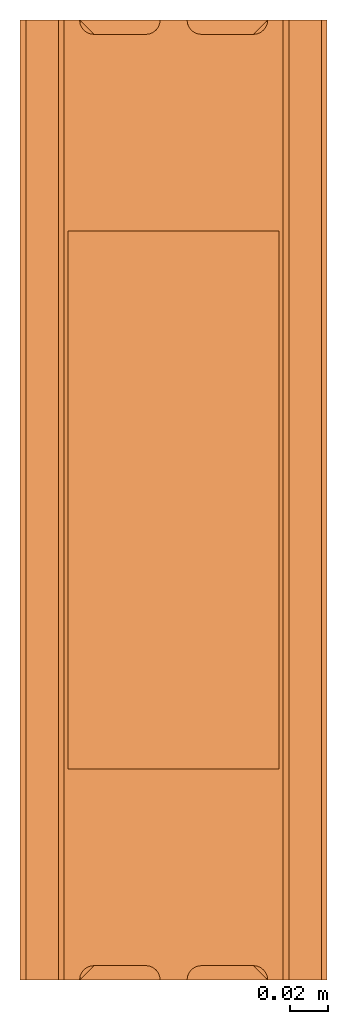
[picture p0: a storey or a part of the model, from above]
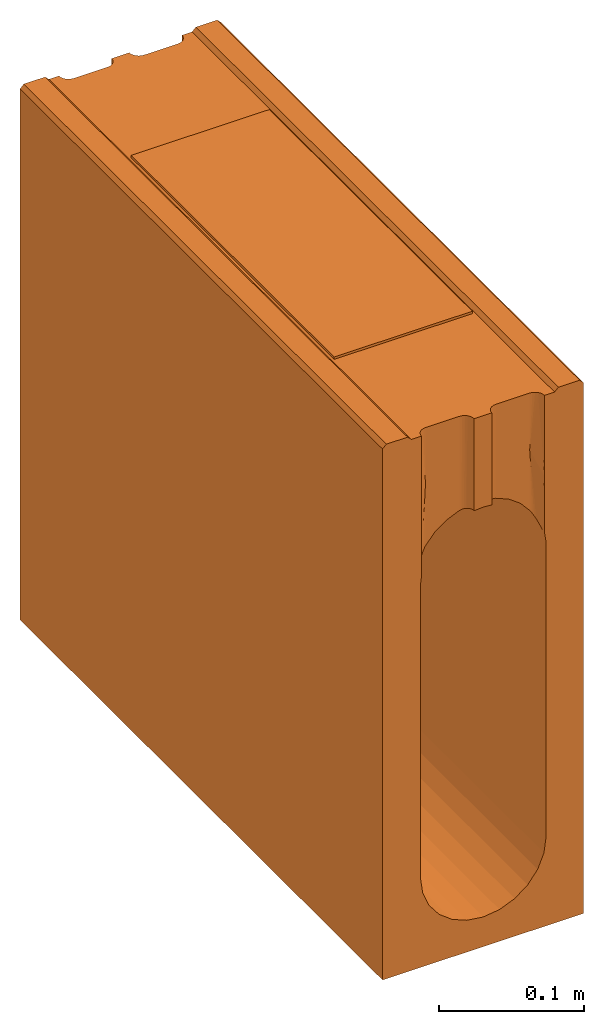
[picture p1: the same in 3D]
Properties of the parts of a building model (IFC2X3)

# File
Description: ViewDefinition [CoordinationView]
File name: 32503 - PD100 F 50.3 Rodding Access 500mm LG.ifc
Time: 2013-10-11T12:33:49
Written by: Autodesk Revit 2013
Made in: 20120221_2030(x64)

# IfcProject, Project Number
LongName: Project Name; Phase: Project Status

# IfcSite, Default
RefLatitude: 42, 21, 30, 344238; RefLongitude: -71, -3, -35, -194702; RefElevation: 0 mm

# IfcBuilding
Pset_BuildingCommon - NumberOfStoreys: 2
Other - Client Name: Owner; Project Number: Project Number; Project Issue Date: Issue Date; Project Status: Project Status; Project Address: Enter address here; Project Name: Project Name

# IfcBuildingStorey (2)
Constraints - Elevation Base: 0
Graphics - Symbol: M_Level Head - Circle: M_Level Head - Circle; Color: 0; Line Pattern: Center; Symbol at End 1 Default: no; Symbol at End 2 Default: yes; Line Weight: 1
Identity Data - Building Story: yes; Structural: no
Dimensions - Computation Height: 0 mm
Name | LongName = Name | Elevation (mm) = Constraints, Elevation (mm)
B.O. Footing | B.O. Footing | -4600
T.O. Footing | T.O. Footing | -4300

# IfcBuildingElementProxy: 32503 - PD100 F 50.3 Rodding Access 500mm LG, Civil-Drainage-Channel-ACO-RoadDrain 100:32503 - PD100 F 50.3 Rodding Access 500mm LG:32503 - PD100 F 50.3 Rodding Access 500mm LG:310733
In: B.O. Footing
Material: Acetal Resin, Black
Other - Revision: 1; CreatedBy: www.aco.co.uk
Dimensions - Invert Depth.: 375 mm; Void Depth: -450 mm; I/O End Cap Void: 3260 mm; Straight Void Start: 0 mm; Total Depth: 450 mm; Custom Void Length: 0 mm; Volume: 19568456 mm3; Straight Void Length: 500 mm; Length: 500 mm
Phasing - Phase Created: Phase 1
Constraints - Level: Level: T.O. Footing; Moves With Nearby Elements: no
Pset_BuildingElementProxyCommon - Reference: 32503 - PD100 F 50.3 Rodding Access 500mm LG
Identity Data - URL: www.aco.co.uk; Product Page URL: http://www.aco.co.uk/product_detail.php?id=21; Type Comments: ACO RoadDrain 100 PD100F 50.3 Constant Depth Access Channel 500mm Long; OmniClass Title: Rainwater Removal; Manufacturer: ACO Technologies plc - ACO Water Management Division; Cost: 0; Model: ACO RoadDrain 100 PD100F; Assembly Code: D2040; e-mail Technical: technical@aco.co.uk; OmniClass Number: 23.70.50.24; Installation guidelines: http://www.aco.co.uk/download.php?id=256; Address: ACO Business Park, Hitchin Road, Shefford, Bedfordshire, United Kingdom SG17 5TE; Product Code: 32503; e-mail Sales: customersupport@aco.co.uk; Model Description: Monolithic Channel drainage system; Price: POA - contact ACO; Maintenance guidelines: http://www.aco.co.uk/download.php?id=256; Watermarked With: BIM Manager Premium Suite; Watermark 1: This file is the property of ACO Technologies PLC; Telephone: +44 (0)1462 816666; Assembly Description: Rain Water Drainage; Watermark 2: This file is water marked and users are prohibited to reproduce, adapt, distribute this information; Fax: +44 (0)1462 815895; Product brochure: http://www.aco.co.uk/download.php?id=256; Watermarked By: www.aco.co.uk
Data - Product Dimensions: 500mm x 160mm x 450mm (LxWxH); Invert Depth: 425mm; Installation - Concrete Grade: Refer to brochure; Concrete Surround Volume - Load Class F 900 - Concrete Pavement: 0.30m³; Connection Pipe O.D: N/A; ACO Hydraulic Design Software: http://www.acodesign.co.uk; Load Class: A 15 - F 900; Channel C.S.A: 0.032m²; Hydraulic Performance: http://www.aco.co.uk/download.php?id=256; Product Weight: 34.6 Kg; Product Standard: BE EN1433:2002, CE Marked, Kitemarked
General - TagNumber: 0.000000; SerialNumber: 0.000000
Materials and Finishes - Access Cover/Frame Finish: Water Based Paint Coating; Grating Material: N/A; Access Cover/Frame Material: Ductile Iron; End Cap Material: N/A; Connection Pipe Material: N/A; Grating Colour: N/A; Grating Finish: N/A; Access Cover/Frame Colour: Black; Channel Colour: Black; End Cap Colour: N/A; Connection Pipe Colour: N/A; Channel Material: Vienite® Synthetic Resin Concrete
Green Building Properties - Channel Recyclable: Fully recyclable; Access Cover/Frame Recyclable: Fully recyclable; Access Cover/Frame Recycled Material Content: Between 40% - 90%; Grating Recycled Material Content: N/A; Channel Recycled Material Content: 20% minimum; Grating Recyclable: N/A; End Cap Recyclable: N/A; End Cap Recycled Material Content: N/A
Construction - Access unit: yes; 32900 - Sump Unit: no; Channel 160mm Wide: no; Grating 500mm: no; Closing End Cap: no; Inlet Outlet end cap_350 high: no; Inlet Outlet end cap_450 high: no

# IfcOpeningElement: Recess (2)
In: T.O. Footing
Dimensions - Perimeter: 22200 mm; Area: 30800000 mm2; Thickness: 1550 mm; Volume: 47704000000 mm3
Constraints - Room Bounding: yes; Level: Level: T.O. Footing; Height Offset From Level: 0 mm; Related to Mass: no
Structural - Structural: no; Enable Analytical Model: no
Phasing - Phase Created: Phase 1
Construction - Function: 0; Default Thickness: 1550 mm
Analytical Properties - Roughness: 1; Thermal mass: 2039700; Thermal Resistance (R): 1.79211; Heat Transfer Coefficient (U): 0.558; Absorptance: 0.1
Materials and Finishes - Structural Material: Grass
Graphics - Coarse Scale Fill Color: 0

# IfcSlab: Floor:Generic Floor - 400mm, Floor:Generic Floor - 400mm:136436
In: T.O. Footing
PredefinedType: FLOOR; Material: Grass 50 mm, Earth 1500 mm
Dimensions - Perimeter: 22200 mm; Area: 30800000 mm2; Thickness: 1550 mm; Volume: 47704000000 mm3
Constraints - Room Bounding: yes; Level: Level: T.O. Footing; Height Offset From Level: 0 mm; Related to Mass: no
Structural - Structural: no; Enable Analytical Model: no
Phasing - Phase Created: Phase 1
Pset_SlabCommon - Reference: Generic Floor - 400mm; IsExternal: no; LoadBearing: yes
Construction - Function: 0; Default Thickness: 1550 mm
Analytical Properties - Roughness: 1; Thermal mass: 2039700; Thermal Resistance (R): 1.79211; Heat Transfer Coefficient (U): 0.558; Absorptance: 0.1
Materials and Finishes - Structural Material: Grass
Graphics - Coarse Scale Fill Color: 0
